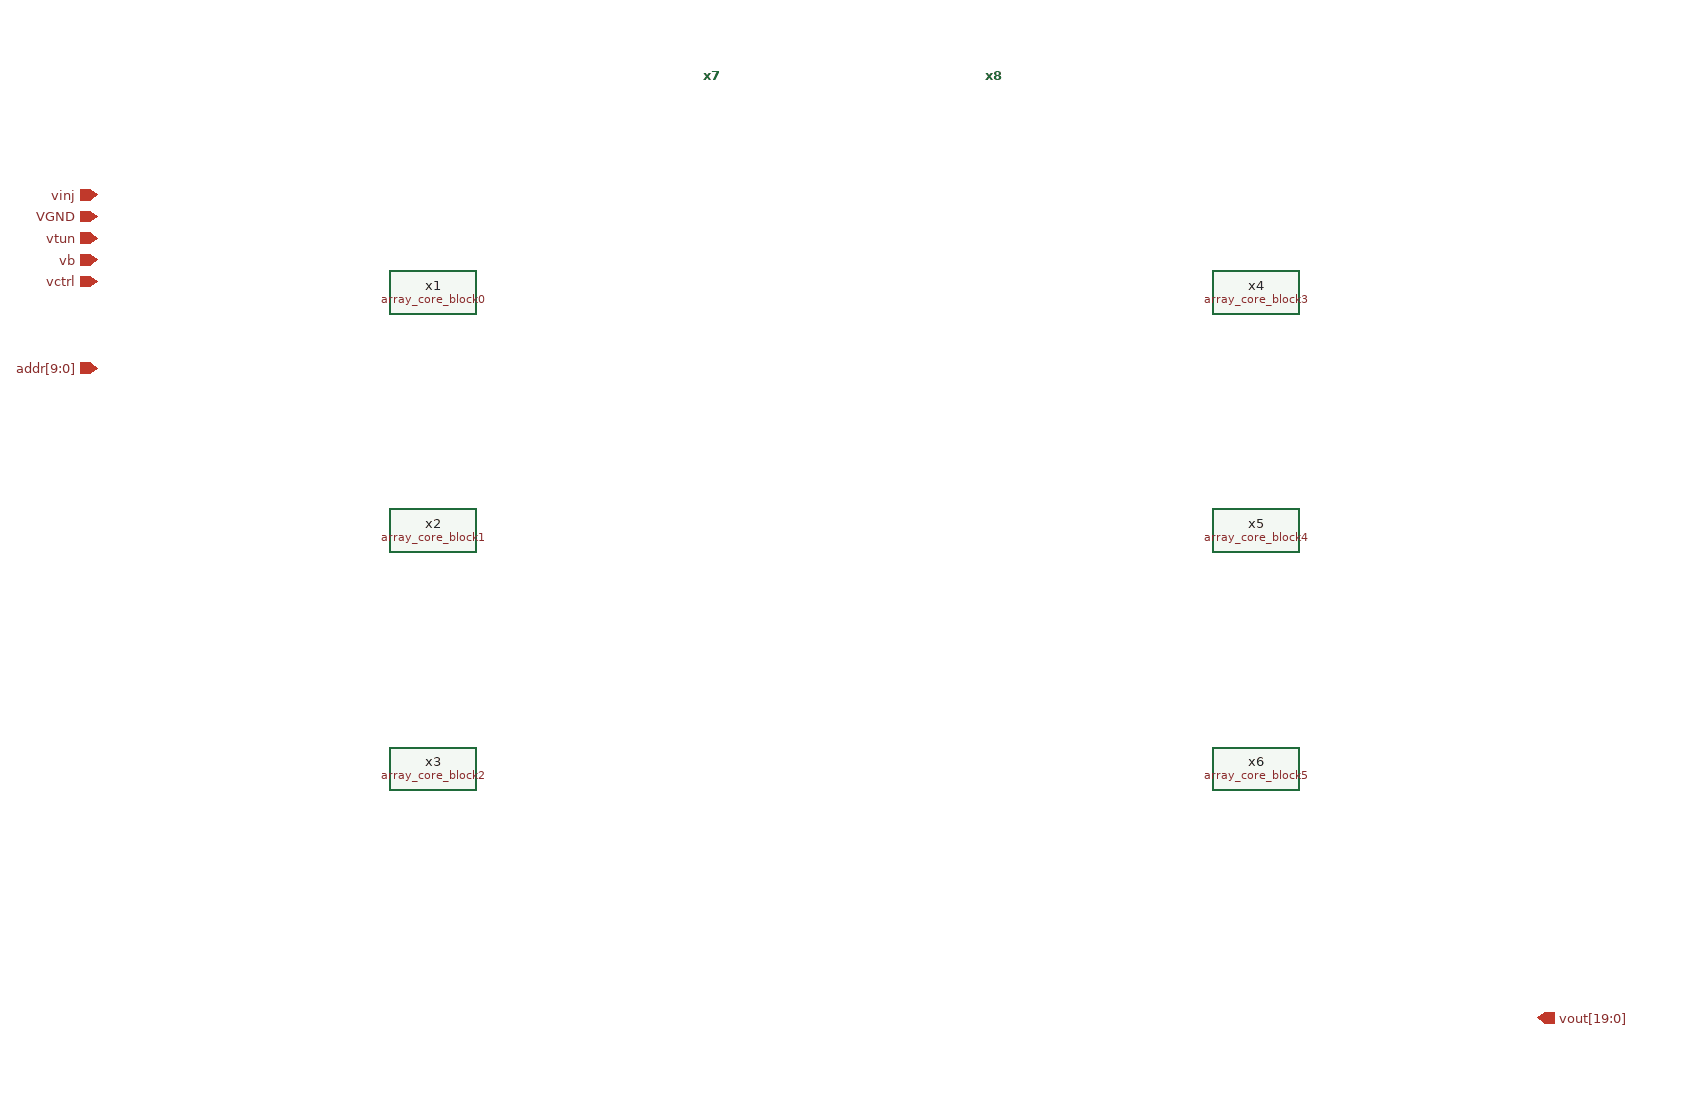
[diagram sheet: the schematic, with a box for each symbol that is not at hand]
v {xschem version=3.4.5 file_version=1.2
}
G {}
K {}
V {}
S {}
E {}
C {array_core_block0.sym} 530 -1010 0 1 {name=x1}
C {array_core_block1.sym} 530 -790 0 1 {name=x2}
C {array_core_block2.sym} 530 -570 0 1 {name=x3}
C {array_core_block3.sym} 1290 -1010 0 0 {name=x4}
C {array_core_block4.sym} 1290 -790 0 0 {name=x5}
C {array_core_block5.sym} 1290 -570 0 0 {name=x6}
C {devices/ipin.sym} 220 -1100 0 0 {name=p1 lab=vinj}
C {devices/ipin.sym} 220 -1080 0 0 {name=p2 lab=VGND}
C {devices/ipin.sym} 220 -1060 0 0 {name=p3 lab=vtun}
C {devices/ipin.sym} 220 -1040 0 0 {name=p4 lab=vb}
C {devices/ipin.sym} 220 -1020 0 0 {name=p5 lab=vctrl}
C {devices/opin.sym} 1550 -340 0 0 {name=p6 lab=vout[19:0]}
C {array_row_decode.sym} 780 -1210 3 1 {name=x7}
C {array_row_decode.sym} 1040 -1210 1 0 {name=x8}
C {devices/ipin.sym} 220 -940 0 0 {name=p7 lab=addr[9:0]}
